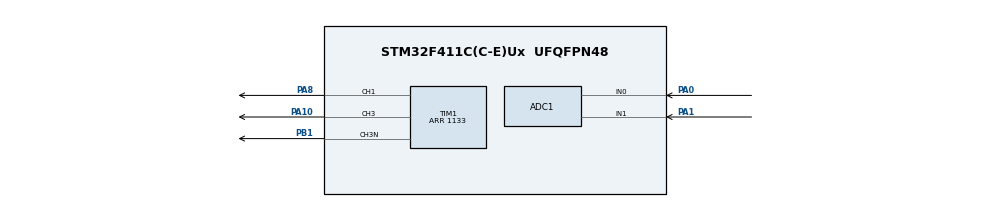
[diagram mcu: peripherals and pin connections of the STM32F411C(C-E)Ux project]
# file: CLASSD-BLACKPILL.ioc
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ADC1.Channel-0\#ChannelRegularConversion=ADC_CHANNEL_0
ADC1.Channel-1\#ChannelRegularConversion=ADC_CHANNEL_1
ADC1.DMAContinuousRequests=ENABLE
ADC1.ExternalTrigConv=ADC_EXTERNALTRIGCONV_T1_CC1
ADC1.NbrOfConversion=2
ADC1.NbrOfConversionFlag=1
ADC1.Rank-0\#ChannelRegularConversion=1
ADC1.Rank-1\#ChannelRegularConversion=2
ADC1.SamplingTime-0\#ChannelRegularConversion=ADC_SAMPLETIME_3CYCLES
ADC1.SamplingTime-1\#ChannelRegularConversion=ADC_SAMPLETIME_3CYCLES
ADC1.ScanConvMode=ENABLE
ADC1.master=1
Dma.ADC1.0.Direction=DMA_PERIPH_TO_MEMORY
Dma.ADC1.0.FIFOMode=DMA_FIFOMODE_DISABLE
Dma.ADC1.0.Instance=DMA2_Stream0
Dma.ADC1.0.MemDataAlignment=DMA_MDATAALIGN_HALFWORD
Dma.ADC1.0.MemInc=DMA_MINC_ENABLE
Dma.ADC1.0.Mode=DMA_CIRCULAR
Dma.ADC1.0.PeriphDataAlignment=DMA_PDATAALIGN_HALFWORD
Dma.ADC1.0.PeriphInc=DMA_PINC_DISABLE
Dma.ADC1.0.Priority=DMA_PRIORITY_LOW
Dma.Request0=ADC1
Mcu.Family=STM32F4
Mcu.Name=STM32F411C(C-E)Ux
Mcu.Package=UFQFPN48
NVIC.DMA2_Stream0_IRQn=true\:0\:0\:false\:false\:true\:false\:true\:true
NVIC.PriorityGroup=NVIC_PRIORITYGROUP_4
PA0-WKUP.Signal=ADCx_IN0
PA1.Signal=ADCx_IN1
PA10.Signal=S_TIM1_CH3
PA8.Signal=S_TIM1_CH1
PB1.Mode=PWM Generation3 CH3 CH3N
PB1.Signal=TIM1_CH3N
PH0\ -\ OSC_IN.Mode=HSE-External-Oscillator
PH0\ -\ OSC_IN.Signal=RCC_OSC_IN
PH1\ -\ OSC_OUT.Mode=HSE-External-Oscillator
PH1\ -\ OSC_OUT.Signal=RCC_OSC_OUT
ProjectManager.HeapSize=0x200
ProjectManager.StackSize=0x400
ProjectManager.TargetToolchain=CMake
RCC.48MHZClocksFreq_Value=50000000
RCC.AHBFreq_Value=100000000
RCC.APB1CLKDivider=RCC_HCLK_DIV2
RCC.APB1Freq_Value=50000000
RCC.APB1TimFreq_Value=100000000
RCC.APB2Freq_Value=100000000
RCC.APB2TimFreq_Value=100000000
RCC.CortexFreq_Value=100000000
RCC.HCLKFreq_Value=100000000
RCC.HSE_VALUE=8000000
RCC.HSI_VALUE=16000000
RCC.LSE_VALUE=32768
RCC.PLLM=8
RCC.PLLN=100
RCC.SYSCLKFreq_VALUE=100000000
RCC.SYSCLKSource=RCC_SYSCLKSOURCE_PLLCLK
RCC.VCOOutputFreq_Value=200000000
SH.ADCx_IN0.0=ADC1_IN0,IN0
SH.ADCx_IN1.0=ADC1_IN1,IN1
SH.S_TIM1_CH1.0=TIM1_CH1,Output Compare1 CH1
SH.S_TIM1_CH3.0=TIM1_CH3,PWM Generation3 CH3 CH3N
TIM1.Channel-Output\ Compare1\ CH1=TIM_CHANNEL_1
TIM1.Channel-PWM\ Generation3\ CH3\ CH3N=TIM_CHANNEL_3
TIM1.DeadTime=20
TIM1.OCMode_1=TIM_OCMODE_TOGGLE
TIM1.Period=1133
TIM1.Pulse-Output\ Compare1\ CH1=0
TIM1.TIM_MasterOutputTrigger=TIM_TRGO_OC1REF
TIM1.TIM_MasterSlaveMode=TIM_MASTERSLAVEMODE_ENABLE
board=custom

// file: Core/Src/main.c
/* USER CODE BEGIN Header */
/**
  ******************************************************************************
  * @file           : main.c
  * @brief          : Main program body
  ******************************************************************************
  * @attention
  *
  * Copyright (c) 2026 STMicroelectronics.
  * All rights reserved.
  *
  * This software is licensed under terms that can be found in the LICENSE file
  * in the root directory of this software component.
  * If no LICENSE file comes with this software, it is provided AS-IS.
  *
  ******************************************************************************
  */
/* USER CODE END Header */
#include "main.h"

/* USER CODE BEGIN PD */
#define arr_value 1133//arr for 44.1kHz
#define INV_4095 (1.0f / 4095.0f*1.2f)
/* USER CODE END PD */

ADC_HandleTypeDef hadc1;
DMA_HandleTypeDef hdma_adc1;

TIM_HandleTypeDef htim1;

/* USER CODE BEGIN PV */
volatile uint16_t adc_val[2];
volatile float max_vol;
/* USER CODE END PV */

void SystemClock_Config(void);
static void MX_GPIO_Init(void);
static void MX_DMA_Init(void);
static void MX_TIM1_Init(void);
static void MX_ADC1_Init(void);

int main(void)
{

  /* MCU Configuration--------------------------------------------------------*/

  /* Reset of all peripherals, Initializes the Flash interface and the Systick. */
  HAL_Init();

  /* Configure the system clock */
  SystemClock_Config();

  /* Initialize all configured peripherals */
  MX_GPIO_Init();
  MX_DMA_Init();
  MX_TIM1_Init();
  MX_ADC1_Init();
  /* USER CODE BEGIN 2 */
HAL_ADC_Start_DMA(&hadc1, (uint32_t*)adc_val, 2);
  HAL_TIM_OC_Start(&htim1, TIM_CHANNEL_1);
HAL_TIM_PWM_Start(&htim1, TIM_CHANNEL_3);
HAL_TIMEx_PWMN_Start(&htim1, TIM_CHANNEL_3);
  /* USER CODE END 2 */

  /* Infinite loop */
  while (1)
  {

    /* USER CODE BEGIN 3 */

    max_vol=((float)(adc_val[1]))*INV_4095;
    uint16_t pwm= (uint16_t)((max_vol*(float)adc_val[0]*(float)arr_value)*INV_4095);
  // adc_top is 4095 and arr_value is the top of duty cycle
  __HAL_TIM_SET_COMPARE(&htim1, TIM_CHANNEL_3,pwm);

  }
  /* USER CODE END 3 */
}

void SystemClock_Config(void)
{
  RCC_OscInitTypeDef RCC_OscInitStruct = {0};
  RCC_ClkInitTypeDef RCC_ClkInitStruct = {0};

  /** Configure the main internal regulator output voltage
  */
  __HAL_RCC_PWR_CLK_ENABLE();
  __HAL_PWR_VOLTAGESCALING_CONFIG(PWR_REGULATOR_VOLTAGE_SCALE1);

  /** Initializes the RCC Oscillators according to the specified parameters
  * in the RCC_OscInitTypeDef structure.
  */
  RCC_OscInitStruct.OscillatorType = RCC_OSCILLATORTYPE_HSE;
  RCC_OscInitStruct.HSEState = RCC_HSE_ON;
  RCC_OscInitStruct.PLL.PLLState = RCC_PLL_ON;
  RCC_OscInitStruct.PLL.PLLSource = RCC_PLLSOURCE_HSE;
  RCC_OscInitStruct.PLL.PLLM = 12;
  RCC_OscInitStruct.PLL.PLLN = 96;
  RCC_OscInitStruct.PLL.PLLP = RCC_PLLP_DIV2;
  RCC_OscInitStruct.PLL.PLLQ = 4;
  if (HAL_RCC_OscConfig(&RCC_OscInitStruct) != HAL_OK)
  {
    Error_Handler();
  }

  /** Initializes the CPU, AHB and APB buses clocks
  */
  RCC_ClkInitStruct.ClockType = RCC_CLOCKTYPE_HCLK|RCC_CLOCKTYPE_SYSCLK
                              |RCC_CLOCKTYPE_PCLK1|RCC_CLOCKTYPE_PCLK2;
  RCC_ClkInitStruct.SYSCLKSource = RCC_SYSCLKSOURCE_PLLCLK;
  RCC_ClkInitStruct.AHBCLKDivider = RCC_SYSCLK_DIV1;
  RCC_ClkInitStruct.APB1CLKDivider = RCC_HCLK_DIV2;
  RCC_ClkInitStruct.APB2CLKDivider = RCC_HCLK_DIV1;

  if (HAL_RCC_ClockConfig(&RCC_ClkInitStruct, FLASH_LATENCY_3) != HAL_OK)
  {
    Error_Handler();
  }
}

static void MX_ADC1_Init(void)
{

  ADC_ChannelConfTypeDef sConfig = {0};

  /** Configure the global features of the ADC (Clock, Resolution, Data Alignment and number of conversion)
  */
  hadc1.Instance = ADC1;
  hadc1.Init.ClockPrescaler = ADC_CLOCK_SYNC_PCLK_DIV4;
  hadc1.Init.Resolution = ADC_RESOLUTION_12B;
  hadc1.Init.ScanConvMode = ENABLE;
  hadc1.Init.ContinuousConvMode = DISABLE;
  hadc1.Init.DiscontinuousConvMode = DISABLE;
  hadc1.Init.ExternalTrigConvEdge = ADC_EXTERNALTRIGCONVEDGE_RISING;
  hadc1.Init.ExternalTrigConv = ADC_EXTERNALTRIGCONV_T1_CC1;
  hadc1.Init.DataAlign = ADC_DATAALIGN_RIGHT;
  hadc1.Init.NbrOfConversion = 2;
  hadc1.Init.DMAContinuousRequests = ENABLE;
  hadc1.Init.EOCSelection = ADC_EOC_SINGLE_CONV;
  if (HAL_ADC_Init(&hadc1) != HAL_OK)
  {
    Error_Handler();
  }

  /** Configure for the selected ADC regular channel its corresponding rank in the sequencer and its sample time.
  */
  sConfig.Channel = ADC_CHANNEL_0;
  sConfig.Rank = 1;
  sConfig.SamplingTime = ADC_SAMPLETIME_3CYCLES;
  if (HAL_ADC_ConfigChannel(&hadc1, &sConfig) != HAL_OK)
  {
    Error_Handler();
  }

  /** Configure for the selected ADC regular channel its corresponding rank in the sequencer and its sample time.
  */
  sConfig.Channel = ADC_CHANNEL_1;
  sConfig.Rank = 2;
  if (HAL_ADC_ConfigChannel(&hadc1, &sConfig) != HAL_OK)
  {
    Error_Handler();
  }

}

static void MX_TIM1_Init(void)
{

  TIM_MasterConfigTypeDef sMasterConfig = {0};
  TIM_OC_InitTypeDef sConfigOC = {0};
  TIM_BreakDeadTimeConfigTypeDef sBreakDeadTimeConfig = {0};

  htim1.Instance = TIM1;
  htim1.Init.Prescaler = 0;
  htim1.Init.CounterMode = TIM_COUNTERMODE_UP;
  htim1.Init.Period = 1133;
  htim1.Init.ClockDivision = TIM_CLOCKDIVISION_DIV1;
  htim1.Init.RepetitionCounter = 0;
  htim1.Init.AutoReloadPreload = TIM_AUTORELOAD_PRELOAD_DISABLE;
  if (HAL_TIM_OC_Init(&htim1) != HAL_OK)
  {
    Error_Handler();
  }
  if (HAL_TIM_PWM_Init(&htim1) != HAL_OK)
  {
    Error_Handler();
  }
  sMasterConfig.MasterOutputTrigger = TIM_TRGO_OC1REF;
  sMasterConfig.MasterSlaveMode = TIM_MASTERSLAVEMODE_ENABLE;
  if (HAL_TIMEx_MasterConfigSynchronization(&htim1, &sMasterConfig) != HAL_OK)
  {
    Error_Handler();
  }
  sConfigOC.OCMode = TIM_OCMODE_TOGGLE;
  sConfigOC.Pulse = 0;
  sConfigOC.OCPolarity = TIM_OCPOLARITY_HIGH;
  sConfigOC.OCNPolarity = TIM_OCNPOLARITY_HIGH;
  sConfigOC.OCFastMode = TIM_OCFAST_DISABLE;
  sConfigOC.OCIdleState = TIM_OCIDLESTATE_RESET;
  sConfigOC.OCNIdleState = TIM_OCNIDLESTATE_RESET;
  if (HAL_TIM_OC_ConfigChannel(&htim1, &sConfigOC, TIM_CHANNEL_1) != HAL_OK)
  {
    Error_Handler();
  }
  sConfigOC.OCMode = TIM_OCMODE_PWM1;
  if (HAL_TIM_PWM_ConfigChannel(&htim1, &sConfigOC, TIM_CHANNEL_3) != HAL_OK)
  {
    Error_Handler();
  }
  sBreakDeadTimeConfig.OffStateRunMode = TIM_OSSR_DISABLE;
  sBreakDeadTimeConfig.OffStateIDLEMode = TIM_OSSI_DISABLE;
  sBreakDeadTimeConfig.LockLevel = TIM_LOCKLEVEL_OFF;
  sBreakDeadTimeConfig.DeadTime = 20;
  sBreakDeadTimeConfig.BreakState = TIM_BREAK_DISABLE;
  sBreakDeadTimeConfig.BreakPolarity = TIM_BREAKPOLARITY_HIGH;
  sBreakDeadTimeConfig.AutomaticOutput = TIM_AUTOMATICOUTPUT_DISABLE;
  if (HAL_TIMEx_ConfigBreakDeadTime(&htim1, &sBreakDeadTimeConfig) != HAL_OK)
  {
    Error_Handler();
  }
  HAL_TIM_MspPostInit(&htim1);

}

static void MX_DMA_Init(void)
{

  /* DMA controller clock enable */
  __HAL_RCC_DMA2_CLK_ENABLE();

  /* DMA interrupt init */
  /* DMA2_Stream0_IRQn interrupt configuration */
  HAL_NVIC_SetPriority(DMA2_Stream0_IRQn, 0, 0);
  HAL_NVIC_EnableIRQ(DMA2_Stream0_IRQn);

}

static void MX_GPIO_Init(void)
{

  /* GPIO Ports Clock Enable */
  __HAL_RCC_GPIOH_CLK_ENABLE();
  __HAL_RCC_GPIOA_CLK_ENABLE();
  __HAL_RCC_GPIOB_CLK_ENABLE();

}

void Error_Handler(void)
{
  __disable_irq();
  while (1)
  {
  }
}
